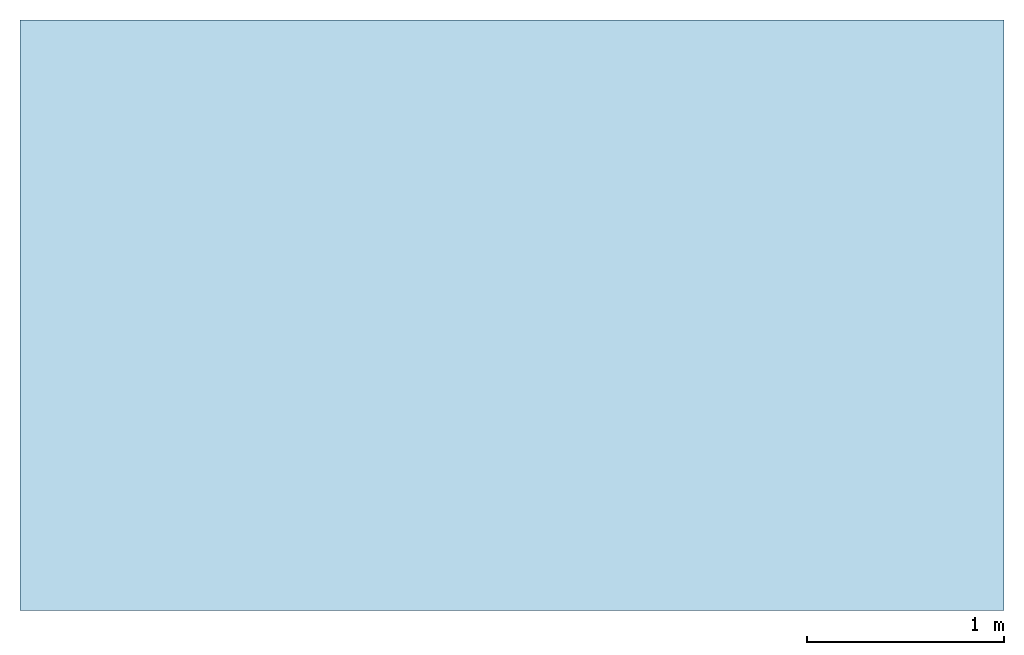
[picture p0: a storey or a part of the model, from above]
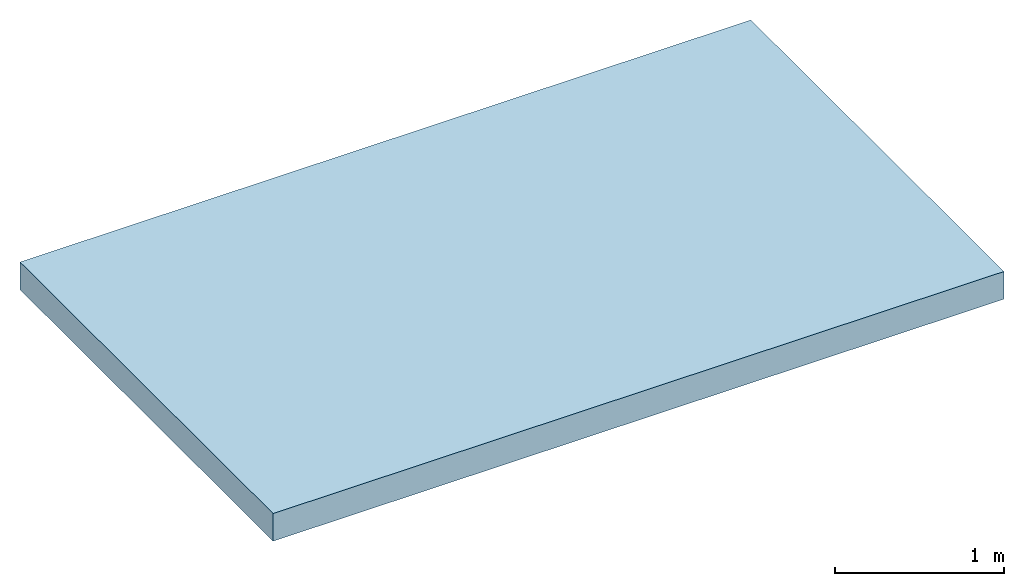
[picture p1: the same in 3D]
Properties of the parts of a building model (IFC4)

# File
Description: no view
File name: ÖBV_OEBV_Richtlinie_Fußbodenaufbau.ifc
Time: 2024-03-13T09:39:24
Author: Oesterreichische Bautechnik Vereinigung
Organization: OEBV
Written by: ODA SDAI 24.5
Authorization: OEBV

# IfcSite, Liegenschaft
RefLatitude: 48, 8, 10, 320000; RefLongitude: 11, 41, 19, 320000

# IfcBuildingStorey (2)
In: Gebäude
Elevation: 0 m
Name
Geschoss 01
Geschoss 02

# IfcSpace, 00.01
In: Geschoss 02
Description: Wohnzimmer; LongName: Wohnen
AllplanAttributes - Allright_Bauteil_ID: 0061Rau0000000022

# IfcBuildingElementProxy (3)
In: Geschoss 02
Name | Allright_Bauteil_ID
FFBOK | 0061Mak0000000009
 | 0061Mak0000000014
macro | 0061Mak0000000019

# IfcCovering (6)
In: 00.01
Name | Description | PredefinedType | Material | Allright_Bauteil_ID
FB 01 | Bodenschicht | FLOORING | Schüttung 0.09 m | 0061Bfl0000000004/01
FB 01 | Bodenschicht | FLOORING | Trittschalldämmung 0.03 m | 0061Bfl0000000004/02
FB 01 | Bodenschicht | FLOORING | PE-Folie 0 m | 0061Bfl0000000004/03
FB 01 | Bodenschicht | FLOORING | Estrich 0.07 m | 0061Bfl0000000004/04
FB 01 | Bodenschicht | FLOORING | Parkett 0.01 m | 0061Bfl0000000004/05
LEI_01 | Leiste | SKIRTINGBOARD | Holz 3cm | 0061Lei0000000005

# IfcElementAssembly (4)
Name | In | Allright_Bauteil_ID
SpatialDim_Group | Geschoss 02 | 0061Elg0000000010
SpatialDim_Group | Geschoss 02 | 0061Elg0000000015
SpatialDim_Group | Geschoss 02 | 0061Elg0000000020
FB 01 | 00.01 | Description: Bodenschicht

# IfcSlab
In: Geschoss 01
PredefinedType: FLOOR
AllplanAttributes - Allright_Bauteil_ID: 0011De 0000005309
